VERSION 5.8 ;
BUSBITCHARS "[]" ;
DIVIDERCHAR "/" ;
UNITS
    DATABASE MICRONS 1000 ;
END UNITS

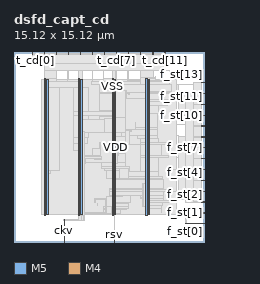
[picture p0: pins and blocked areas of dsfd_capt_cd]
MACRO dsfd_capt_cd
  FOREIGN dsfd_capt_cd 0 0 ;
  CLASS BLOCK ;
  SIZE 15.12 BY 15.12 ;
  PIN ckv
    DIRECTION INPUT ;
    USE SIGNAL ;
    PORT
      LAYER M5 ;
        RECT  3.984 0 4.008 0.192 ;
    END
    PORT
      LAYER M5 ;
        RECT  3.984 0.144 4.008 1.763 ;
    END
  END ckv
  PIN f_st[0]
    DIRECTION INPUT ;
    USE SIGNAL ;
    PORT
      LAYER M4 ;
        RECT  14.928 1.44 15.12 1.464 ;
    END
    PORT
      LAYER M4 ;
        RECT  13.669 1.44 14.94 1.464 ;
    END
  END f_st[0]
  PIN f_st[10]
    DIRECTION INPUT ;
    USE SIGNAL ;
    PORT
      LAYER M4 ;
        RECT  14.928 10.08 15.12 10.104 ;
    END
  END f_st[10]
  PIN f_st[11]
    DIRECTION INPUT ;
    USE SIGNAL ;
    PORT
      LAYER M4 ;
        RECT  14.928 10.944 15.12 10.968 ;
    END
  END f_st[11]
  PIN f_st[12]
    DIRECTION INPUT ;
    USE SIGNAL ;
    PORT
      LAYER M4 ;
        RECT  14.928 11.808 15.12 11.832 ;
    END
  END f_st[12]
  PIN f_st[13]
    DIRECTION INPUT ;
    USE SIGNAL ;
    PORT
      LAYER M4 ;
        RECT  14.928 12.672 15.12 12.696 ;
    END
  END f_st[13]
  PIN f_st[1]
    DIRECTION INPUT ;
    USE SIGNAL ;
    PORT
      LAYER M4 ;
        RECT  14.928 2.304 15.12 2.328 ;
    END
  END f_st[1]
  PIN f_st[2]
    DIRECTION INPUT ;
    USE SIGNAL ;
    PORT
      LAYER M4 ;
        RECT  14.928 3.168 15.12 3.192 ;
    END
  END f_st[2]
  PIN f_st[3]
    DIRECTION INPUT ;
    USE SIGNAL ;
    PORT
      LAYER M4 ;
        RECT  14.928 4.032 15.12 4.056 ;
    END
  END f_st[3]
  PIN f_st[4]
    DIRECTION INPUT ;
    USE SIGNAL ;
    PORT
      LAYER M4 ;
        RECT  14.928 4.896 15.12 4.92 ;
    END
  END f_st[4]
  PIN f_st[5]
    DIRECTION INPUT ;
    USE SIGNAL ;
    PORT
      LAYER M4 ;
        RECT  14.928 5.76 15.12 5.784 ;
    END
  END f_st[5]
  PIN f_st[6]
    DIRECTION INPUT ;
    USE SIGNAL ;
    PORT
      LAYER M4 ;
        RECT  14.928 6.624 15.12 6.648 ;
    END
  END f_st[6]
  PIN f_st[7]
    DIRECTION INPUT ;
    USE SIGNAL ;
    PORT
      LAYER M4 ;
        RECT  14.928 7.488 15.12 7.512 ;
    END
  END f_st[7]
  PIN f_st[8]
    DIRECTION INPUT ;
    USE SIGNAL ;
    PORT
      LAYER M4 ;
        RECT  14.928 8.352 15.12 8.376 ;
    END
  END f_st[8]
  PIN f_st[9]
    DIRECTION INPUT ;
    USE SIGNAL ;
    PORT
      LAYER M4 ;
        RECT  14.928 9.216 15.12 9.24 ;
    END
  END f_st[9]
  PIN rsv
    DIRECTION INPUT ;
    USE SIGNAL ;
    PORT
      LAYER M5 ;
        RECT  7.968 0 7.992 0.192 ;
    END
    PORT
      LAYER M5 ;
        RECT  7.968 0.144 7.992 0.611 ;
    END
  END rsv
  PIN t_cd[0]
    DIRECTION OUTPUT ;
    USE SIGNAL ;
    PORT
      LAYER M5 ;
        RECT  1.44 14.928 1.464 15.12 ;
    END
  END t_cd[0]
  PIN t_cd[10]
    DIRECTION OUTPUT ;
    USE SIGNAL ;
    PORT
      LAYER M5 ;
        RECT  11.04 14.928 11.064 15.12 ;
    END
  END t_cd[10]
  PIN t_cd[11]
    DIRECTION OUTPUT ;
    USE SIGNAL ;
    PORT
      LAYER M5 ;
        RECT  12 14.928 12.024 15.12 ;
    END
  END t_cd[11]
  PIN t_cd[1]
    DIRECTION OUTPUT ;
    USE SIGNAL ;
    PORT
      LAYER M5 ;
        RECT  2.4 14.928 2.424 15.12 ;
    END
  END t_cd[1]
  PIN t_cd[2]
    DIRECTION OUTPUT ;
    USE SIGNAL ;
    PORT
      LAYER M5 ;
        RECT  3.36 14.928 3.384 15.12 ;
    END
  END t_cd[2]
  PIN t_cd[3]
    DIRECTION OUTPUT ;
    USE SIGNAL ;
    PORT
      LAYER M5 ;
        RECT  4.32 14.928 4.344 15.12 ;
    END
  END t_cd[3]
  PIN t_cd[4]
    DIRECTION OUTPUT ;
    USE SIGNAL ;
    PORT
      LAYER M5 ;
        RECT  5.28 14.928 5.304 15.12 ;
    END
  END t_cd[4]
  PIN t_cd[5]
    DIRECTION OUTPUT ;
    USE SIGNAL ;
    PORT
      LAYER M5 ;
        RECT  6.24 14.928 6.264 15.12 ;
    END
  END t_cd[5]
  PIN t_cd[6]
    DIRECTION OUTPUT ;
    USE SIGNAL ;
    PORT
      LAYER M5 ;
        RECT  7.2 14.928 7.224 15.12 ;
    END
  END t_cd[6]
  PIN t_cd[7]
    DIRECTION OUTPUT ;
    USE SIGNAL ;
    PORT
      LAYER M5 ;
        RECT  8.16 14.928 8.184 15.12 ;
    END
  END t_cd[7]
  PIN t_cd[8]
    DIRECTION OUTPUT ;
    USE SIGNAL ;
    PORT
      LAYER M5 ;
        RECT  9.12 14.928 9.144 15.12 ;
    END
  END t_cd[8]
  PIN t_cd[9]
    DIRECTION OUTPUT ;
    USE SIGNAL ;
    PORT
      LAYER M5 ;
        RECT  10.08 14.928 10.104 15.12 ;
    END
  END t_cd[9]
  PIN VDD
    DIRECTION INOUT ;
    USE POWER ;
    PORT
      LAYER M5 ;
        RECT  10.692 2.151 10.812 12.969 ;
        RECT  7.992 2.151 8.112 12.969 ;
        RECT  5.292 2.151 5.412 12.969 ;
        RECT  2.592 2.151 2.712 12.969 ;
    END
  END VDD
  PIN VSS
    DIRECTION INOUT ;
    USE GROUND ;
    PORT
      LAYER M5 ;
        RECT  10.5 2.137 10.62 12.983 ;
        RECT  7.8 2.137 7.92 12.983 ;
        RECT  5.1 2.137 5.22 12.983 ;
        RECT  2.4 2.137 2.52 12.983 ;
    END
  END VSS
  # OT_OBS_CLOSED layer=M5 d_um=1.536 added=2
  OBS
    LAYER RVTN ;
     RECT  2.16 2.16 12.96 2.295 ;
     RECT  2.16 2.565 12.96 2.835 ;
     RECT  2.16 3.105 12.96 3.375 ;
     RECT  2.16 3.645 12.96 3.915 ;
     RECT  2.16 4.185 12.96 4.455 ;
     RECT  2.16 4.725 12.96 4.995 ;
     RECT  2.16 5.265 12.96 5.535 ;
     RECT  2.16 5.805 12.96 6.075 ;
     RECT  2.16 6.345 12.96 6.615 ;
     RECT  2.16 6.885 12.96 7.155 ;
     RECT  2.16 7.425 12.96 7.695 ;
     RECT  2.16 7.965 12.96 8.235 ;
     RECT  2.16 8.505 12.96 8.775 ;
     RECT  2.16 9.045 12.96 9.315 ;
     RECT  2.16 9.585 12.96 9.855 ;
     RECT  2.16 10.125 12.96 10.395 ;
     RECT  2.16 10.665 12.96 10.935 ;
     RECT  2.16 11.205 12.96 11.475 ;
     RECT  2.16 11.745 12.96 12.015 ;
     RECT  2.16 12.285 12.96 12.555 ;
     RECT  2.16 12.825 12.96 12.96 ;
    LAYER RVTP ;
     RECT  2.16 2.295 12.96 2.565 ;
     RECT  2.16 2.835 12.96 3.105 ;
     RECT  2.16 3.375 12.96 3.645 ;
     RECT  2.16 3.915 12.96 4.185 ;
     RECT  2.16 4.455 12.96 4.725 ;
     RECT  2.16 4.995 12.96 5.265 ;
     RECT  2.16 5.535 12.96 5.805 ;
     RECT  2.16 6.075 12.96 6.345 ;
     RECT  2.16 6.615 12.96 6.885 ;
     RECT  2.16 7.155 12.96 7.425 ;
     RECT  2.16 7.695 12.96 7.965 ;
     RECT  2.16 8.235 12.96 8.505 ;
     RECT  2.16 8.775 12.96 9.045 ;
     RECT  2.16 9.315 12.96 9.585 ;
     RECT  2.16 9.855 12.96 10.125 ;
     RECT  2.16 10.395 12.96 10.665 ;
     RECT  2.16 10.935 12.96 11.205 ;
     RECT  2.16 11.475 12.96 11.745 ;
     RECT  2.16 12.015 12.96 12.285 ;
     RECT  2.16 12.555 12.96 12.825 ;
    LAYER M1 ;
     RECT  2.16 2.151 12.96 12.969 ;
    LAYER M2 ;
     RECT  2.16 2.151 12.96 12.969 ;
     RECT  12.96 4.968 13.127 4.986 ;
     RECT  12.96 6.696 13.127 6.714 ;
     RECT  12.96 7.668 13.127 7.686 ;
     RECT  12.96 8.478 13.127 8.496 ;
     RECT  12.96 11.25 13.127 12.546 ;
     RECT  12.96 2.268 13.703 2.286 ;
     RECT  12.96 3.348 13.703 3.366 ;
     RECT  12.96 9.36 13.703 9.378 ;
     RECT  13.127 12.528 14.279 12.546 ;
    LAYER M3 ;
     RECT  7.992 0.571 8.01 2.143 ;
     RECT  5.115 2.143 5.205 2.191 ;
     RECT  7.815 2.143 8.01 2.191 ;
     RECT  13.68 1.435 13.698 2.291 ;
     RECT  7.815 2.191 8.442 2.299 ;
     RECT  5.115 2.191 5.706 2.333 ;
     RECT  2.415 2.143 2.505 2.413 ;
     RECT  10.515 2.143 10.605 2.413 ;
     RECT  7.092 2.299 8.442 2.605 ;
     RECT  7.092 2.605 8.946 2.641 ;
     RECT  10.515 2.413 10.797 2.641 ;
     RECT  11.7 2.371 11.718 2.641 ;
     RECT  7.092 2.641 9.09 2.861 ;
     RECT  10.515 2.641 11.718 2.911 ;
     RECT  6.624 2.911 6.642 3.029 ;
     RECT  7.38 2.861 9.09 3.065 ;
     RECT  7.416 3.065 9.09 3.101 ;
     RECT  7.632 3.101 9.09 3.181 ;
     RECT  10.515 2.911 11.826 3.181 ;
     RECT  12.6 3.145 12.618 3.181 ;
     RECT  10.515 3.181 12.618 3.299 ;
     RECT  13.68 3.163 13.698 3.371 ;
     RECT  6.444 3.109 6.462 3.437 ;
     RECT  10.515 3.299 11.898 3.451 ;
     RECT  10.296 3.451 11.898 3.499 ;
     RECT  7.632 3.181 9.27 3.685 ;
     RECT  10.044 3.499 11.898 3.685 ;
     RECT  7.632 3.685 11.898 4.027 ;
     RECT  7.632 4.027 12.582 4.181 ;
     RECT  7.632 4.181 11.934 4.289 ;
     RECT  7.815 4.289 11.934 4.991 ;
     RECT  13.104 4.891 13.122 4.991 ;
     RECT  7.815 4.991 11.826 5.035 ;
     RECT  7.38 5.035 11.826 5.072 ;
     RECT  9.144 5.072 11.826 5.189 ;
     RECT  9.144 5.189 11.754 5.225 ;
     RECT  2.415 2.413 2.697 5.467 ;
     RECT  9.144 5.225 11.538 5.639 ;
     RECT  2.415 5.467 2.898 5.701 ;
     RECT  7.38 5.072 8.406 5.701 ;
     RECT  12.564 5.755 12.582 5.801 ;
     RECT  7.236 5.701 8.406 5.881 ;
     RECT  9.144 5.639 9.162 5.881 ;
     RECT  6.984 5.881 9.162 5.999 ;
     RECT  5.115 2.333 5.397 6.283 ;
     RECT  6.984 5.999 8.91 6.317 ;
     RECT  5.115 6.283 5.67 6.619 ;
     RECT  6.444 6.547 6.93 6.619 ;
     RECT  10.08 5.639 11.538 6.691 ;
     RECT  13.104 6.619 13.122 6.719 ;
     RECT  5.115 6.619 6.93 6.809 ;
     RECT  5.115 6.809 6.858 6.845 ;
     RECT  10.08 6.691 12.258 6.845 ;
     RECT  7.815 6.317 8.91 7.079 ;
     RECT  5.115 6.845 5.397 7.321 ;
     RECT  6.228 6.845 6.858 7.421 ;
     RECT  10.08 6.845 11.754 7.771 ;
     RECT  4.716 7.321 5.397 7.861 ;
     RECT  6.84 7.421 6.858 7.889 ;
     RECT  10.08 7.771 12.222 7.925 ;
     RECT  10.08 7.925 11.502 8.239 ;
     RECT  9.792 8.239 11.502 8.267 ;
     RECT  7.815 7.079 8.514 8.275 ;
     RECT  4.716 7.861 5.886 8.311 ;
     RECT  7.815 8.275 8.55 8.311 ;
     RECT  7.815 8.311 9.018 8.437 ;
     RECT  9.792 8.267 11.43 8.437 ;
     RECT  13.104 7.483 13.122 8.501 ;
     RECT  7.815 8.437 11.43 8.969 ;
     RECT  7.815 8.969 8.694 9.041 ;
     RECT  9.648 8.969 11.43 9.113 ;
     RECT  7.815 9.041 8.622 9.319 ;
     RECT  13.68 9.211 13.698 9.383 ;
     RECT  6.804 8.851 6.822 9.391 ;
     RECT  7.776 9.319 8.622 9.391 ;
     RECT  9.648 9.113 9.666 9.545 ;
     RECT  6.804 9.391 8.622 9.787 ;
     RECT  6.804 9.787 8.838 9.965 ;
     RECT  4.716 8.311 5.958 10.057 ;
     RECT  6.804 9.965 8.586 10.057 ;
     RECT  12.564 10.075 12.582 10.193 ;
     RECT  10.515 9.113 11.43 10.201 ;
     RECT  4.716 10.057 8.586 10.355 ;
     RECT  6.804 10.355 8.586 10.427 ;
     RECT  10.515 10.201 11.502 10.867 ;
     RECT  10.515 10.867 12.222 11.209 ;
     RECT  10.44 11.209 12.222 11.371 ;
     RECT  13.104 10.939 13.122 11.371 ;
     RECT  6.804 10.427 8.097 11.785 ;
     RECT  9.144 11.713 9.162 11.785 ;
     RECT  10.44 11.371 13.122 11.837 ;
     RECT  6.804 11.785 9.162 11.911 ;
     RECT  10.44 11.837 12.546 11.911 ;
     RECT  4.716 10.355 5.958 12.289 ;
     RECT  4.356 12.289 5.958 12.317 ;
     RECT  2.415 5.701 3.582 12.325 ;
     RECT  4.356 12.317 5.454 12.325 ;
     RECT  6.804 11.911 12.546 12.523 ;
     RECT  6.192 12.523 12.546 12.551 ;
     RECT  14.256 12.523 14.274 12.701 ;
     RECT  2.415 12.325 5.454 12.749 ;
     RECT  6.192 12.551 12.366 12.749 ;
     RECT  6.228 12.749 8.118 12.785 ;
     RECT  9.072 12.749 12.366 12.821 ;
     RECT  10.515 12.821 12.366 12.857 ;
     RECT  4.284 12.749 5.454 12.929 ;
     RECT  2.415 12.749 3.402 12.977 ;
     RECT  5.115 12.929 5.454 12.977 ;
     RECT  7.092 12.785 8.118 12.977 ;
     RECT  10.515 12.857 11.25 12.977 ;
     RECT  2.736 12.977 3.402 13.085 ;
     RECT  2.736 13.085 2.79 13.133 ;
     RECT  11.232 12.977 11.25 13.133 ;
     RECT  4.284 12.929 4.302 13.661 ;
     RECT  5.436 12.977 5.454 13.661 ;
     RECT  6.228 12.785 6.246 13.661 ;
     RECT  7.092 12.977 7.11 13.661 ;
     RECT  12.348 12.857 12.366 13.661 ;
     RECT  8.1 12.977 8.118 13.709 ;
     RECT  9.072 12.821 9.09 13.709 ;
     RECT  2.736 13.133 2.754 14.237 ;
    LAYER M4 ;
     RECT  2.389 13.104 2.408 13.128 ;
     RECT  2.408 2.148 2.512 13.128 ;
     RECT  2.512 2.418 2.704 13.128 ;
     RECT  1.429 14.208 2.765 14.232 ;
     RECT  2.704 13.056 2.801 13.128 ;
     RECT  2.801 13.056 3.413 13.08 ;
     RECT  3.973 1.728 5.108 1.752 ;
     RECT  4.273 13.632 5.108 13.656 ;
     RECT  5.108 1.728 5.404 13.656 ;
     RECT  5.404 1.728 5.603 2.328 ;
     RECT  5.404 8.736 7.225 9.72 ;
     RECT  5.603 2.304 7.297 2.328 ;
     RECT  6.433 3.408 7.297 3.432 ;
     RECT  7.297 2.304 7.381 3.432 ;
     RECT  7.381 2.304 7.729 3.624 ;
     RECT  7.729 2.304 7.808 3.72 ;
     RECT  7.369 5.04 7.808 5.064 ;
     RECT  5.404 6.288 7.808 6.312 ;
     RECT  7.225 8.736 7.808 9.816 ;
     RECT  7.441 12.048 7.808 12.072 ;
     RECT  5.404 13.632 7.808 13.656 ;
     RECT  7.808 2.148 7.912 13.656 ;
     RECT  7.937 0.576 8.021 0.6 ;
     RECT  7.912 2.418 8.104 12.702 ;
     RECT  8.104 6.288 8.243 9.96 ;
     RECT  8.243 6.864 8.309 9.96 ;
     RECT  8.104 3.6 8.633 3.72 ;
     RECT  8.104 5.04 8.849 5.064 ;
     RECT  8.309 7.728 8.849 9.96 ;
     RECT  8.849 9.936 8.867 9.96 ;
     RECT  8.104 11.424 8.913 12.072 ;
     RECT  8.089 13.68 9.155 13.704 ;
     RECT  8.849 7.728 9.173 8.856 ;
     RECT  9.173 8.832 9.389 8.856 ;
     RECT  8.633 3.696 10.033 3.72 ;
     RECT  10.033 3.504 10.261 3.72 ;
     RECT  10.261 2.832 10.508 4.68 ;
     RECT  9.173 7.728 10.508 7.752 ;
     RECT  8.913 11.424 10.508 11.448 ;
     RECT  10.069 12.528 10.508 12.552 ;
     RECT  10.508 2.148 10.612 12.972 ;
     RECT  10.612 2.418 10.804 12.972 ;
     RECT  11.029 13.104 11.261 13.128 ;
     RECT  11.989 13.632 12.377 13.656 ;
     RECT  10.804 11.952 12.557 11.976 ;
     RECT  12.553 4.032 13.093 4.056 ;
     RECT  12.553 5.76 13.093 5.784 ;
     RECT  12.553 10.08 13.093 10.104 ;
     RECT  13.093 4.032 13.669 8.376 ;
     RECT  13.093 10.08 13.669 11.832 ;
     RECT  13.669 3.168 14.245 11.832 ;
     RECT  14.245 3.168 14.928 3.192 ;
     RECT  14.245 3.192 14.94 4.032 ;
     RECT  14.245 4.032 14.928 4.056 ;
     RECT  14.245 4.056 14.94 4.896 ;
     RECT  14.245 4.896 14.928 4.92 ;
     RECT  14.245 4.92 14.94 5.76 ;
     RECT  14.245 5.76 14.928 5.784 ;
     RECT  14.245 5.784 14.94 6.624 ;
     RECT  14.245 6.624 14.928 6.648 ;
     RECT  14.245 6.648 14.94 7.488 ;
     RECT  14.245 7.488 14.928 7.512 ;
     RECT  14.245 7.512 14.94 8.352 ;
     RECT  14.245 8.352 14.928 8.376 ;
     RECT  14.245 8.376 14.94 9.216 ;
     RECT  14.245 9.216 14.928 9.24 ;
     RECT  14.245 9.24 14.94 10.08 ;
     RECT  14.245 10.08 14.928 10.104 ;
     RECT  14.245 10.104 14.94 10.944 ;
     RECT  14.245 10.944 14.928 10.968 ;
     RECT  14.245 10.968 14.94 11.808 ;
     RECT  14.245 11.808 14.928 11.832 ;
     RECT  14.245 11.832 14.94 12.672 ;
     RECT  14.245 12.672 14.928 12.696 ;
    LAYER M5 ;
     RECT  5.568 1.717 5.592 2.137 ;
     RECT  2.4 2.137 2.52 2.151 ;
     RECT  7.8 2.137 7.92 2.151 ;
     RECT  10.5 2.137 10.62 2.151 ;
     RECT  7.8 2.151 8.112 2.821 ;
     RECT  10.5 2.151 10.812 2.821 ;
     RECT  7.392 2.821 8.112 3.635 ;
     RECT  10.272 2.821 10.812 4.691 ;
     RECT  7.8 3.635 8.112 6.277 ;
     RECT  7.8 6.277 8.232 7.717 ;
     RECT  7.8 7.717 8.856 8.435 ;
     RECT  7.8 8.435 8.568 8.675 ;
     RECT  5.1 2.137 5.592 8.771 ;
     RECT  7.8 8.675 8.112 9.925 ;
     RECT  7.8 9.925 8.856 12.083 ;
     RECT  10.5 4.691 10.812 12.517 ;
     RECT  2.4 2.151 2.712 13.045 ;
     RECT  10.08 12.517 10.812 13.093 ;
     RECT  2.4 13.045 3.384 13.621 ;
     RECT  5.1 8.771 5.412 13.621 ;
     RECT  7.8 12.083 8.112 13.621 ;
     RECT  10.08 13.093 11.064 13.621 ;
     RECT  2.4 13.621 8.112 13.669 ;
     RECT  10.08 13.621 12.024 13.669 ;
     RECT  2.4 13.669 12.024 14.197 ;
     RECT  1.44 14.197 12.024 14.928 ;
     RECT  1.464 14.928 2.4 14.992 ;
     RECT  2.424 14.928 3.36 14.992 ;
     RECT  3.384 14.928 4.32 14.992 ;
     RECT  4.344 14.928 5.28 14.992 ;
     RECT  5.304 14.928 6.24 14.992 ;
     RECT  6.264 14.928 7.2 14.992 ;
     RECT  7.224 14.928 8.16 14.992 ;
     RECT  8.184 14.928 9.12 14.992 ;
     RECT  9.144 14.928 10.08 14.992 ;
     RECT  10.104 14.928 11.04 14.992 ;
     RECT  11.064 14.928 12 14.992 ;
     RECT  8.568 8.435 8.856 8.675 ;
     RECT  8.112 8.675 8.856 9.925 ;
  END
END dsfd_capt_cd
END LIBRARY
